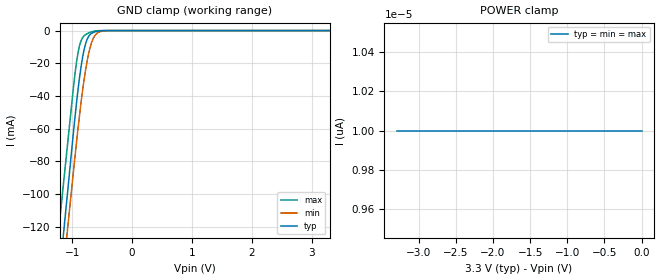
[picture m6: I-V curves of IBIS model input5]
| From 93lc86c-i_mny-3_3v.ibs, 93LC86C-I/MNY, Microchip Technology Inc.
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|   Model input5
[Model]   input5
Model_type   Input
Vinl = 0.8
Vinh = 2.0
C_comp   5.00pF   5.00pF   5.00pF
[Temperature Range]   25.00   85.00   -40.00
[Voltage Range]   3.30V   2.50V   5.50V
[Pullup Reference]   3.30V   3.30V   3.30V
[POWER Clamp Reference]   3.30V   3.30V   3.30V
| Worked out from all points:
|   GND clamp passes 1 mA (typ) near -0.64 V on its own axis
[GND_clamp]
| voltage   I(typ)   I(min)   I(max)
-3.3V     -931.6mA   -920.3mA   -855.9mA
-1.26V    -167.9mA   -187.5mA   -134.5mA
-1.175V   -136mA     -157mA     -104.5mA
-1.09V    -104.2mA   -126.4mA   -74.39mA
-975mV    -61.15mA   -85.14mA   -33.73mA
-925mV    -43.69mA   -67.77mA   -18.88mA
-875mV    -28.4mA    -51.49mA   -9.012mA
-825mV    -16.25mA   -36.52mA   -4.315mA
-750mV    -5.447mA   -18.82mA   -1.925mA
-650mV    -1.198mA   -4.979mA   -534.4uA
-475mV    -43.23uA   -230.6uA   -2.486uA
3.3V      10pA       10pA       10pA
[POWER_clamp]
| voltage   I(typ)   I(min)   I(max)
-3.3V     10pA       10pA       10pA
-3.23V    10pA       10pA       10pA
-3.16V    10pA       10pA       10pA
0V        10pA       10pA       10pA
